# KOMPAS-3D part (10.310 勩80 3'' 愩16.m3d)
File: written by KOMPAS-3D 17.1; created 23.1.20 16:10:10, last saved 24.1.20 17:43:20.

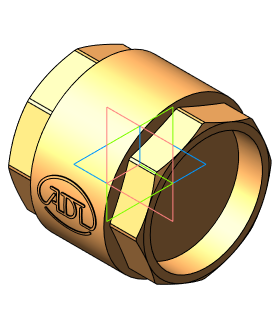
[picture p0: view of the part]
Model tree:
1. Операция без истории:2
